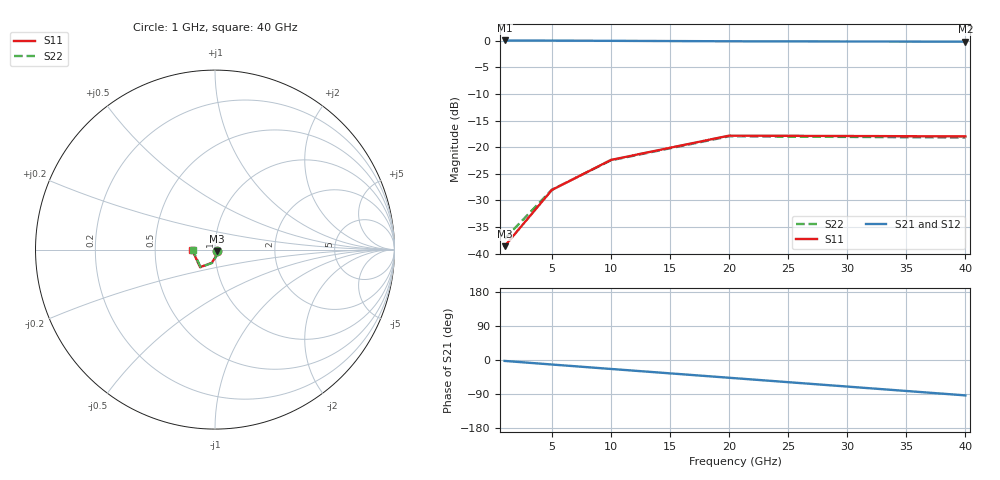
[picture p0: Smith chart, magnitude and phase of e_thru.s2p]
! Generated by circuitRF - EM: EMerge
! circuitRF-EM setup: g_thru_sheets
! circuitRF-EM layout: thru/layout/thru.clay
! circuitRF-EM written: 2026-11-05 00:40:10Z
! circuitRF-EM geometry: e7095096f2ddb833
! circuitRF-EM mesh: ae32805cddc33b92
! circuitRF-EM ports: 1a591d5b5a03db7b
! circuitRF-EM model: EMerge 3.0.0b2
! Port[1] = port/1
! Port[2] = port/2
! circuitRF-EM port 1: 'port/1' from 'airbox/zmin' to 'Metal1/1', lumped, 50 Ohm
! circuitRF-EM port 2: 'port/2' from 'airbox/zmin' to 'Metal1/1', lumped, 50 Ohm
! circuitRF-EM 3D mesh: 3037 tetrahedra, element order 2
! circuitRF-EM 3D operating temperature: 20 C
! circuitRF-EM 3D run: preset Standard; 3037 tetrahedra; 21308 unknowns; 5 frequency sample(s)
! circuitRF-EM 3D run cost: wall 5 s; EMerge peak memory 1.4 GB
! circuitRF-EM 3D DC row: circuitRF conduction solve of the conductors, 368 elements, 0.06 s; ports as terminal pairs
! circuitRF-EM: re-running the EM setup rewrites this file. If circuitRF reports it as stale, the layout's cross-section changed after this file was written.
# GHz S RI R 50
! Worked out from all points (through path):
!   5 points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, 1 GHz to 40 GHz, reference 50 ohm
!   highest |S21| = 0.08 dB at 1 GHz (marker M1); lowest = -0.1 dB at 40 GHz (marker M2)
!   lowest |S11| = -38.6 dB at 1 GHz (marker M3), VSWR 1.02, Z = 50.9 - j0.761 ohm
!   |S11| at or under -10 dB: start of sweep to end of sweep
!   |S22| runs from -37.2 to -18.0 dB; largest |S21 - S12| = 0.0029
1  0.00903 -0.00748  1.008 -0.0426  1.006 -0.0425  0.0116 -0.00746
5  0.00352 -0.0394  0.9842 -0.2076  0.9818 -0.2071  0.00609 -0.0394
10  -0.0178 -0.0738  0.9172 -0.4015  0.9149 -0.4004  -0.0152 -0.0737
20  -0.0831 -0.0979  0.6777 -0.7232  0.676 -0.7213  -0.0803 -0.0978
40  -0.1263 -0.0032  -0.0581 -0.9814  -0.0577 -0.9786  -0.1232 -0.00379
